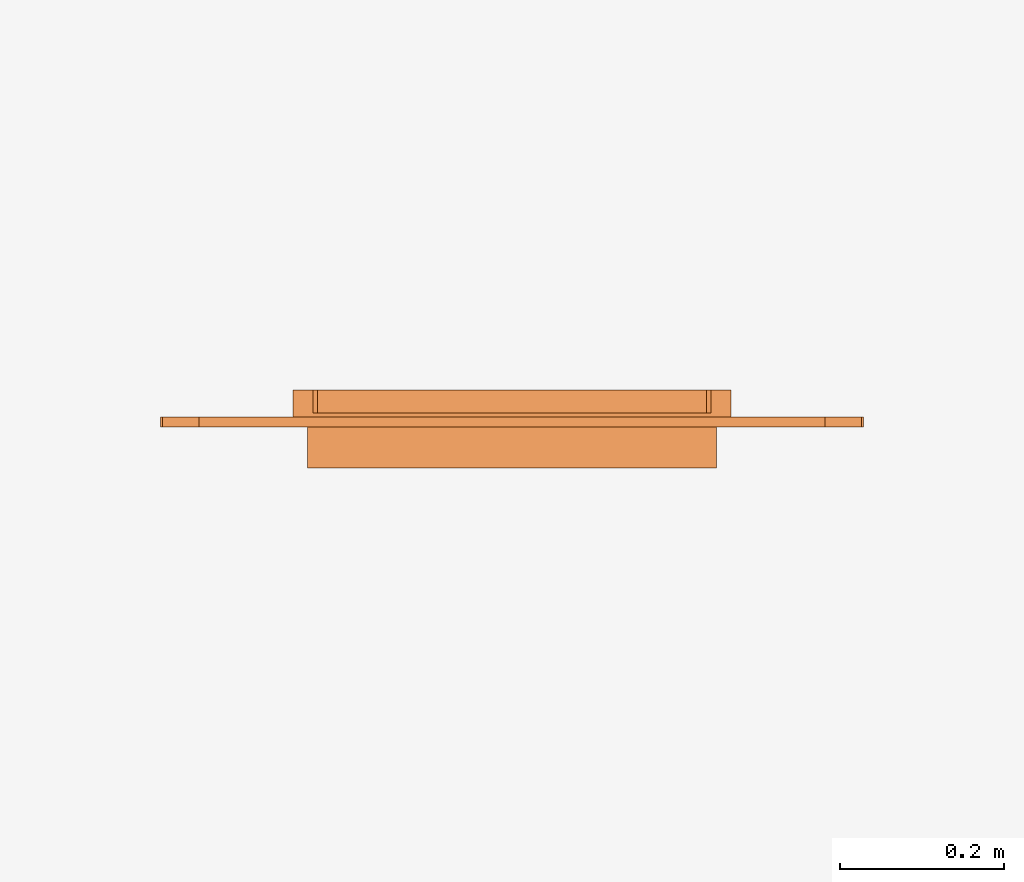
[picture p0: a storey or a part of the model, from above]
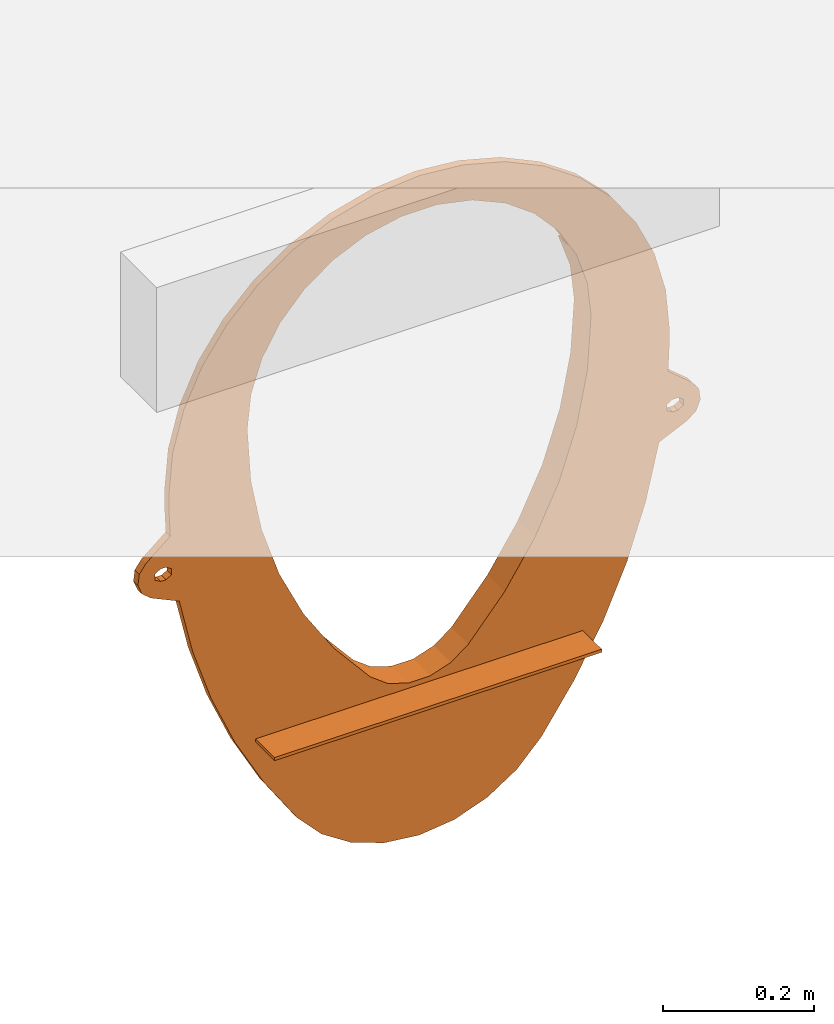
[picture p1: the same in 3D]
Properties of the parts of a building model (IFC2X3)

# File
Description: ViewDefinition [CoordinationView]
File name: 32883 - 700-900 Step Connector.ifc
Time: 2013-07-12T10:25:22
Written by: Autodesk Revit 2013
Made in: 20120221_2030(x64)

# IfcProject, Project Number
LongName: Project Name; Phase: Project Status

# IfcSite, Default
RefLatitude: 42, 21, 30, 344238; RefLongitude: -71, -3, -35, -194702; RefElevation: 0 mm

# IfcBuilding
Pset_BuildingCommon - NumberOfStoreys: 1
Other - Project Address: ## Street City, State Zip; Project Issue Date: Issue Date; Project Number: Project Number; Client Name: Owner; Project Name: Project Name; Project Status: Project Status

# IfcBuildingStorey, Level 1
LongName: Level 1; Elevation: 0 mm
Constraints - Elevation Base: 0; Elevation: 0 mm
Graphics - Line Weight: 1; Symbol at End 2 Default: yes; Color: 0; Symbol at End 1 Default: no; Line Pattern: Center; Symbol: M_Level Head - Circle: M_Level Head - Circle
Dimensions - Computation Height: 0 mm
Identity Data - Building Story: yes; Name: Level 1; Structural: no

# IfcBuildingElementProxy: 700-900 Step_Connector, 700-900 Step_Connector:700-900 Step_Connector:700-900 Step_Connector:521072
In: Level 1
Phasing - Phase Created: New Construction
Dimensions - Volume: 4418605 mm3; Centre_Depth: 680.5 mm
Constraints - Moves With Nearby Elements: no; Level: Level: Level 1
Pset_BuildingElementProxyCommon - Reference: 700-900 Step_Connector

# IfcOpeningElement: Opening
In: Level 1
Structural - Enable Analytical Model: no; Structural: no
Constraints - Level: Level: Level 1; Related to Mass: no; Height Offset From Level: 0 mm; Room Bounding: yes
Dimensions - Thickness: 400 mm; Area: 135090000 mm2; Volume: 54019537443 mm3; Perimeter: 50000 mm
Phasing - Phase Created: New Construction
Analytical Properties - Absorptance: 0.1; Roughness: 1
Graphics - Coarse Scale Fill Color: 0
Construction - Function: 0; Default Thickness: 400 mm
Materials and Finishes - Structural Material: Plant

# IfcSlab: Floor:Generic Floor - 400mm, Floor:Generic Floor - 400mm:193825
In: Level 1
PredefinedType: FLOOR; Material: Plant 400 mm
Structural - Enable Analytical Model: no; Structural: no
Constraints - Level: Level: Level 1; Related to Mass: no; Height Offset From Level: 0 mm; Room Bounding: yes
Dimensions - Thickness: 400 mm; Area: 135090000 mm2; Volume: 54019537443 mm3; Perimeter: 50000 mm
Phasing - Phase Created: New Construction
Pset_SlabCommon - Reference: Generic Floor - 400mm; IsExternal: no; LoadBearing: yes
Analytical Properties - Absorptance: 0.1; Roughness: 1
Graphics - Coarse Scale Fill Color: 0
Construction - Function: 0; Default Thickness: 400 mm
Materials and Finishes - Structural Material: Plant
